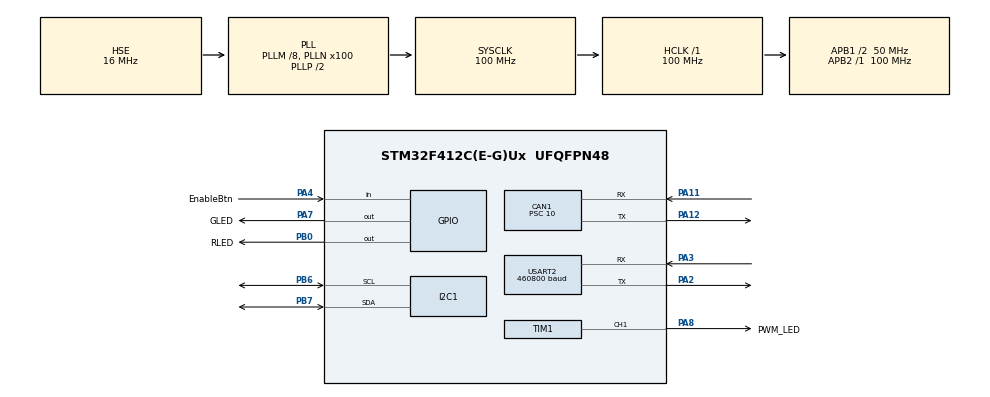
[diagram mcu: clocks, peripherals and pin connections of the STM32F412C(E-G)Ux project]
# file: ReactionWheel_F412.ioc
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CAN1.ABOM=ENABLE
CAN1.BS1=CAN_BS1_8TQ
CAN1.CalculateBaudRate=500000
CAN1.CalculateTimeBit=2000
CAN1.CalculateTimeQuantum=200.0
CAN1.NART=ENABLE
CAN1.Prescaler=10
Dma.Request0=USART2_TX
Dma.USART2_TX.0.Direction=DMA_MEMORY_TO_PERIPH
Dma.USART2_TX.0.FIFOMode=DMA_FIFOMODE_DISABLE
Dma.USART2_TX.0.Instance=DMA1_Stream6
Dma.USART2_TX.0.MemDataAlignment=DMA_MDATAALIGN_BYTE
Dma.USART2_TX.0.MemInc=DMA_MINC_ENABLE
Dma.USART2_TX.0.Mode=DMA_NORMAL
Dma.USART2_TX.0.PeriphDataAlignment=DMA_PDATAALIGN_BYTE
Dma.USART2_TX.0.PeriphInc=DMA_PINC_DISABLE
Dma.USART2_TX.0.Priority=DMA_PRIORITY_VERY_HIGH
I2C1.I2C_Mode=I2C_Fast
Mcu.Family=STM32F4
Mcu.Name=STM32F412C(E-G)Ux
Mcu.Package=UFQFPN48
NVIC.CAN1_RX0_IRQn=true\:0\:0\:false\:false\:true\:true\:true\:true
NVIC.DMA1_Stream6_IRQn=true\:0\:0\:false\:false\:true\:false\:true\:true
NVIC.PriorityGroup=NVIC_PRIORITYGROUP_4
PA11.Mode=CAN_Activate
PA11.Signal=CAN1_RX
PA12.Mode=CAN_Activate
PA12.Signal=CAN1_TX
PA13.Mode=Trace_Asynchronous_SW
PA13.Signal=SYS_JTMS-SWDIO
PA14.Mode=Trace_Asynchronous_SW
PA14.Signal=SYS_JTCK-SWCLK
PA2.Mode=Asynchronous
PA2.Signal=USART2_TX
PA3.Mode=Asynchronous
PA3.Signal=USART2_RX
PA4.GPIO_Label=EnableBtn
PA4.Signal=GPIO_Input
PA7.GPIO_Label=GLED
PA7.GPIO_ModeDefaultOutputPP=GPIO_MODE_OUTPUT_PP
PA7.GPIO_PuPd=GPIO_PULLDOWN
PA7.GPIO_Speed=GPIO_SPEED_FREQ_HIGH
PA7.PinState=GPIO_PIN_RESET
PA7.Signal=GPIO_Output
PA8.GPIO_Label=PWM_LED
PA8.Signal=S_TIM1_CH1
PB0.GPIO_Label=RLED
PB0.GPIO_PuPd=GPIO_PULLDOWN
PB0.GPIO_Speed=GPIO_SPEED_FREQ_HIGH
PB0.PinState=GPIO_PIN_RESET
PB0.Signal=GPIO_Output
PB3.Mode=Trace_Asynchronous_SW
PB3.Signal=SYS_JTDO-SWO
PB6.Mode=I2C
PB6.Signal=I2C1_SCL
PB7.Mode=I2C
PB7.Signal=I2C1_SDA
PH0\ -\ OSC_IN.Mode=HSE-External-Oscillator
PH0\ -\ OSC_IN.Signal=RCC_OSC_IN
PH1\ -\ OSC_OUT.Mode=HSE-External-Oscillator
PH1\ -\ OSC_OUT.Signal=RCC_OSC_OUT
ProjectManager.HeapSize=0x200
ProjectManager.StackSize=0x400
ProjectManager.TargetToolchain=STM32CubeIDE
RCC.AHBFreq_Value=100000000
RCC.APB1CLKDivider=RCC_HCLK_DIV2
RCC.APB1Freq_Value=50000000
RCC.APB1TimFreq_Value=100000000
RCC.APB2Freq_Value=100000000
RCC.APB2TimFreq_Value=100000000
RCC.CortexFreq_Value=100000000
RCC.HCLKFreq_Value=100000000
RCC.HSE_VALUE=16000000
RCC.PLLM=8
RCC.PLLN=100
RCC.PLLSourceVirtual=RCC_PLLSOURCE_HSE
RCC.SYSCLKFreq_VALUE=100000000
RCC.SYSCLKSource=RCC_SYSCLKSOURCE_PLLCLK
RCC.USBFreq_Value=100000000
RCC.VCOOutputFreq_Value=200000000
SH.S_TIM1_CH1.0=TIM1_CH1,PWM Generation1 CH1
STMicroelectronics.X-CUBE-ALGOBUILD.1.3.0.LibraryCcDSPOoLibraryJjDSPOoLibrary=true
TIM1.Channel-PWM\ Generation1\ CH1=TIM_CHANNEL_1
USART2.BaudRate=460800
USART2.Mode=MODE_TX
USART2.VirtualMode=VM_ASYNC
VP_STMicroelectronics.X-CUBE-ALGOBUILD_VS_DSPOoLibraryJjLibrary_1.3.0_1.3.0.Mode=DSPOoLibraryJjLibrary
VP_TIM1_VS_ClockSourceINT.Mode=Internal
board=custom

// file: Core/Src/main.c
/* USER CODE BEGIN Header */
/**
  ******************************************************************************
  * @file           : main.c
  * @brief          : Main program body
  ******************************************************************************
  * @attention
  *
  * Copyright (c) 2023 STMicroelectronics.
  * All rights reserved.
  *
  * This software is licensed under terms that can be found in the LICENSE file
  * in the root directory of this software component.
  * If no LICENSE file comes with this software, it is provided AS-IS.
  *
  ******************************************************************************
  */
/* USER CODE END Header */
#include "main.h"

CAN_HandleTypeDef hcan1;

I2C_HandleTypeDef hi2c1;

TIM_HandleTypeDef htim1;

UART_HandleTypeDef huart2;

void SystemClock_Config(void);
static void MX_GPIO_Init(void);
static void MX_CAN1_Init(void);
static void MX_I2C1_Init(void);
static void MX_USART2_UART_Init(void);
static void MX_TIM1_Init(void);

int main(void)
{

  /* MCU Configuration--------------------------------------------------------*/

  /* Reset of all peripherals, Initializes the Flash interface and the Systick. */
  HAL_Init();

  /* Configure the system clock */
  SystemClock_Config();

  /* Initialize all configured peripherals */
  MX_GPIO_Init();
  MX_CAN1_Init();
  MX_I2C1_Init();
  MX_USART2_UART_Init();
  MX_TIM1_Init();

  /* Infinite loop */
  while (1)
  {

  }
}

void SystemClock_Config(void)
{
  RCC_OscInitTypeDef RCC_OscInitStruct = {0};
  RCC_ClkInitTypeDef RCC_ClkInitStruct = {0};

  /** Configure the main internal regulator output voltage
  */
  __HAL_RCC_PWR_CLK_ENABLE();
  __HAL_PWR_VOLTAGESCALING_CONFIG(PWR_REGULATOR_VOLTAGE_SCALE1);

  /** Initializes the RCC Oscillators according to the specified parameters
  * in the RCC_OscInitTypeDef structure.
  */
  RCC_OscInitStruct.OscillatorType = RCC_OSCILLATORTYPE_HSE;
  RCC_OscInitStruct.HSEState = RCC_HSE_ON;
  RCC_OscInitStruct.PLL.PLLState = RCC_PLL_ON;
  RCC_OscInitStruct.PLL.PLLSource = RCC_PLLSOURCE_HSE;
  RCC_OscInitStruct.PLL.PLLM = 8;
  RCC_OscInitStruct.PLL.PLLN = 100;
  RCC_OscInitStruct.PLL.PLLP = RCC_PLLP_DIV2;
  RCC_OscInitStruct.PLL.PLLQ = 2;
  RCC_OscInitStruct.PLL.PLLR = 2;
  if (HAL_RCC_OscConfig(&RCC_OscInitStruct) != HAL_OK)
  {
    Error_Handler();
  }

  /** Initializes the CPU, AHB and APB buses clocks
  */
  RCC_ClkInitStruct.ClockType = RCC_CLOCKTYPE_HCLK|RCC_CLOCKTYPE_SYSCLK
                              |RCC_CLOCKTYPE_PCLK1|RCC_CLOCKTYPE_PCLK2;
  RCC_ClkInitStruct.SYSCLKSource = RCC_SYSCLKSOURCE_PLLCLK;
  RCC_ClkInitStruct.AHBCLKDivider = RCC_SYSCLK_DIV1;
  RCC_ClkInitStruct.APB1CLKDivider = RCC_HCLK_DIV2;
  RCC_ClkInitStruct.APB2CLKDivider = RCC_HCLK_DIV1;

  if (HAL_RCC_ClockConfig(&RCC_ClkInitStruct, FLASH_LATENCY_3) != HAL_OK)
  {
    Error_Handler();
  }
}

static void MX_CAN1_Init(void)
{

  hcan1.Instance = CAN1;
  hcan1.Init.Prescaler = 16;
  hcan1.Init.Mode = CAN_MODE_NORMAL;
  hcan1.Init.SyncJumpWidth = CAN_SJW_1TQ;
  hcan1.Init.TimeSeg1 = CAN_BS1_1TQ;
  hcan1.Init.TimeSeg2 = CAN_BS2_1TQ;
  hcan1.Init.TimeTriggeredMode = DISABLE;
  hcan1.Init.AutoBusOff = DISABLE;
  hcan1.Init.AutoWakeUp = DISABLE;
  hcan1.Init.AutoRetransmission = DISABLE;
  hcan1.Init.ReceiveFifoLocked = DISABLE;
  hcan1.Init.TransmitFifoPriority = DISABLE;
  if (HAL_CAN_Init(&hcan1) != HAL_OK)
  {
    Error_Handler();
  }

}

static void MX_I2C1_Init(void)
{

  hi2c1.Instance = I2C1;
  hi2c1.Init.ClockSpeed = 100000;
  hi2c1.Init.DutyCycle = I2C_DUTYCYCLE_2;
  hi2c1.Init.OwnAddress1 = 0;
  hi2c1.Init.AddressingMode = I2C_ADDRESSINGMODE_7BIT;
  hi2c1.Init.DualAddressMode = I2C_DUALADDRESS_DISABLE;
  hi2c1.Init.OwnAddress2 = 0;
  hi2c1.Init.GeneralCallMode = I2C_GENERALCALL_DISABLE;
  hi2c1.Init.NoStretchMode = I2C_NOSTRETCH_DISABLE;
  if (HAL_I2C_Init(&hi2c1) != HAL_OK)
  {
    Error_Handler();
  }

}

static void MX_TIM1_Init(void)
{

  TIM_ClockConfigTypeDef sClockSourceConfig = {0};
  TIM_MasterConfigTypeDef sMasterConfig = {0};
  TIM_OC_InitTypeDef sConfigOC = {0};
  TIM_BreakDeadTimeConfigTypeDef sBreakDeadTimeConfig = {0};

  htim1.Instance = TIM1;
  htim1.Init.Prescaler = 0;
  htim1.Init.CounterMode = TIM_COUNTERMODE_UP;
  htim1.Init.Period = 65535;
  htim1.Init.ClockDivision = TIM_CLOCKDIVISION_DIV1;
  htim1.Init.RepetitionCounter = 0;
  htim1.Init.AutoReloadPreload = TIM_AUTORELOAD_PRELOAD_DISABLE;
  if (HAL_TIM_Base_Init(&htim1) != HAL_OK)
  {
    Error_Handler();
  }
  sClockSourceConfig.ClockSource = TIM_CLOCKSOURCE_INTERNAL;
  if (HAL_TIM_ConfigClockSource(&htim1, &sClockSourceConfig) != HAL_OK)
  {
    Error_Handler();
  }
  if (HAL_TIM_PWM_Init(&htim1) != HAL_OK)
  {
    Error_Handler();
  }
  sMasterConfig.MasterOutputTrigger = TIM_TRGO_RESET;
  sMasterConfig.MasterSlaveMode = TIM_MASTERSLAVEMODE_DISABLE;
  if (HAL_TIMEx_MasterConfigSynchronization(&htim1, &sMasterConfig) != HAL_OK)
  {
    Error_Handler();
  }
  sConfigOC.OCMode = TIM_OCMODE_PWM1;
  sConfigOC.Pulse = 0;
  sConfigOC.OCPolarity = TIM_OCPOLARITY_HIGH;
  sConfigOC.OCNPolarity = TIM_OCNPOLARITY_HIGH;
  sConfigOC.OCFastMode = TIM_OCFAST_DISABLE;
  sConfigOC.OCIdleState = TIM_OCIDLESTATE_RESET;
  sConfigOC.OCNIdleState = TIM_OCNIDLESTATE_RESET;
  if (HAL_TIM_PWM_ConfigChannel(&htim1, &sConfigOC, TIM_CHANNEL_1) != HAL_OK)
  {
    Error_Handler();
  }
  sBreakDeadTimeConfig.OffStateRunMode = TIM_OSSR_DISABLE;
  sBreakDeadTimeConfig.OffStateIDLEMode = TIM_OSSI_DISABLE;
  sBreakDeadTimeConfig.LockLevel = TIM_LOCKLEVEL_OFF;
  sBreakDeadTimeConfig.DeadTime = 0;
  sBreakDeadTimeConfig.BreakState = TIM_BREAK_DISABLE;
  sBreakDeadTimeConfig.BreakPolarity = TIM_BREAKPOLARITY_HIGH;
  sBreakDeadTimeConfig.AutomaticOutput = TIM_AUTOMATICOUTPUT_DISABLE;
  if (HAL_TIMEx_ConfigBreakDeadTime(&htim1, &sBreakDeadTimeConfig) != HAL_OK)
  {
    Error_Handler();
  }
  HAL_TIM_MspPostInit(&htim1);

}

static void MX_USART2_UART_Init(void)
{

  huart2.Instance = USART2;
  huart2.Init.BaudRate = 115200;
  huart2.Init.WordLength = UART_WORDLENGTH_8B;
  huart2.Init.StopBits = UART_STOPBITS_1;
  huart2.Init.Parity = UART_PARITY_NONE;
  huart2.Init.Mode = UART_MODE_TX_RX;
  huart2.Init.HwFlowCtl = UART_HWCONTROL_NONE;
  huart2.Init.OverSampling = UART_OVERSAMPLING_16;
  if (HAL_UART_Init(&huart2) != HAL_OK)
  {
    Error_Handler();
  }

}

static void MX_GPIO_Init(void)
{
  GPIO_InitTypeDef GPIO_InitStruct = {0};

  /* GPIO Ports Clock Enable */
  __HAL_RCC_GPIOH_CLK_ENABLE();
  __HAL_RCC_GPIOA_CLK_ENABLE();
  __HAL_RCC_GPIOB_CLK_ENABLE();

  /*Configure GPIO pin Output Level */
  HAL_GPIO_WritePin(GPIOA, GPIO_PIN_7, GPIO_PIN_RESET);

  /*Configure GPIO pins : PA4 PA5 PA6 */
  GPIO_InitStruct.Pin = GPIO_PIN_4|GPIO_PIN_5|GPIO_PIN_6;
  GPIO_InitStruct.Mode = GPIO_MODE_INPUT;
  GPIO_InitStruct.Pull = GPIO_NOPULL;
  HAL_GPIO_Init(GPIOA, &GPIO_InitStruct);

  /*Configure GPIO pin : PA7 */
  GPIO_InitStruct.Pin = GPIO_PIN_7;
  GPIO_InitStruct.Mode = GPIO_MODE_OUTPUT_PP;
  GPIO_InitStruct.Pull = GPIO_NOPULL;
  GPIO_InitStruct.Speed = GPIO_SPEED_FREQ_LOW;
  HAL_GPIO_Init(GPIOA, &GPIO_InitStruct);

}

void Error_Handler(void)
{
  __disable_irq();
  while (1)
  {
  }
}
